VERSION 5.8 ;
BUSBITCHARS "[]" ;
DIVIDERCHAR "/" ;
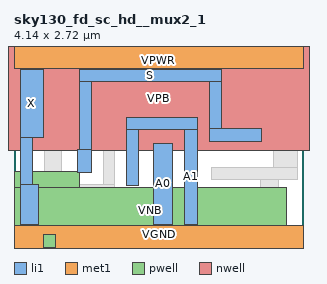
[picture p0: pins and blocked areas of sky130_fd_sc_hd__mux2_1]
MACRO sky130_fd_sc_hd__mux2_1
  CLASS CORE ;
  FOREIGN sky130_fd_sc_hd__mux2_1 ;
  ORIGIN 0.000 0.000 ;
  SIZE 4.140 BY 2.720 ;
  SYMMETRY X Y R90 ;
  SITE unithd ;
  PIN A0
    DIRECTION INPUT ;
    USE SIGNAL ;
    ANTENNAGATEAREA 0.126000 ;
    PORT
      LAYER li1 ;
        RECT 1.990 0.255 2.265 1.415 ;
    END
  END A0
  PIN A1
    DIRECTION INPUT ;
    USE SIGNAL ;
    ANTENNAGATEAREA 0.126000 ;
    PORT
      LAYER li1 ;
        RECT 1.615 1.615 2.625 1.785 ;
        RECT 1.615 0.815 1.785 1.615 ;
        RECT 2.435 0.255 2.625 1.615 ;
    END
  END A1
  PIN S
    DIRECTION INPUT ;
    USE SIGNAL ;
    ANTENNAGATEAREA 0.252000 ;
    PORT
      LAYER li1 ;
        RECT 0.935 2.295 2.965 2.465 ;
        RECT 0.935 1.325 1.105 2.295 ;
        RECT 2.795 1.630 2.965 2.295 ;
        RECT 2.795 1.440 3.545 1.630 ;
        RECT 0.910 0.995 1.105 1.325 ;
    END
  END S
  PIN VGND
    DIRECTION INOUT ;
    USE GROUND ;
    SHAPE ABUTMENT ;
    PORT
      LAYER met1 ;
        RECT 0.000 -0.240 4.140 0.240 ;
    END
  END VGND
  PIN VNB
    DIRECTION INOUT ;
    USE GROUND ;
    PORT
      LAYER pwell ;
        RECT 0.005 0.785 0.935 1.015 ;
        RECT 0.005 0.105 3.905 0.785 ;
        RECT 0.420 -0.085 0.590 0.105 ;
    END
  END VNB
  PIN VPB
    DIRECTION INOUT ;
    USE POWER ;
    PORT
      LAYER nwell ;
        RECT -0.190 1.305 4.330 2.910 ;
    END
  END VPB
  PIN VPWR
    DIRECTION INOUT ;
    USE POWER ;
    SHAPE ABUTMENT ;
    PORT
      LAYER met1 ;
        RECT 0.000 2.480 4.140 2.960 ;
    END
  END VPWR
  PIN X
    DIRECTION OUTPUT ;
    USE SIGNAL ;
    ANTENNADIFFAREA 0.429000 ;
    PORT
      LAYER li1 ;
        RECT 0.090 1.495 0.425 2.465 ;
        RECT 0.090 0.825 0.260 1.495 ;
        RECT 0.090 0.255 0.345 0.825 ;
    END
  END X
  OBS
      LAYER li1 ;
        RECT 0.000 2.635 4.140 2.805 ;
        RECT 0.595 1.495 0.765 2.635 ;
        RECT 1.275 1.955 2.400 2.125 ;
        RECT 0.430 0.995 0.685 1.325 ;
        RECT 0.515 0.825 0.685 0.995 ;
        RECT 1.275 0.825 1.445 1.955 ;
        RECT 3.135 1.875 3.305 2.635 ;
        RECT 3.540 1.875 4.055 2.285 ;
        RECT 3.715 1.065 4.055 1.875 ;
        RECT 2.825 0.895 4.055 1.065 ;
        RECT 0.515 0.655 1.445 0.825 ;
        RECT 1.270 0.620 1.445 0.655 ;
        RECT 0.515 0.085 0.845 0.485 ;
        RECT 1.270 0.255 1.800 0.620 ;
        RECT 2.805 0.085 3.315 0.620 ;
        RECT 3.535 0.290 3.780 0.895 ;
        RECT 0.000 -0.085 4.140 0.085 ;
  END
END sky130_fd_sc_hd__mux2_1
END LIBRARY
